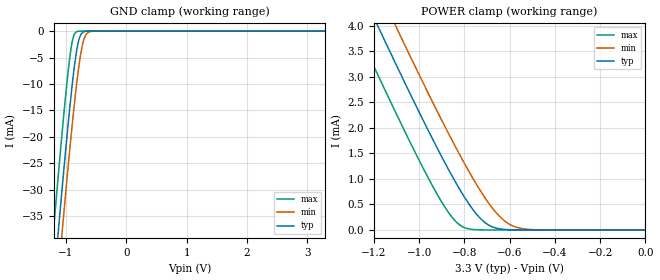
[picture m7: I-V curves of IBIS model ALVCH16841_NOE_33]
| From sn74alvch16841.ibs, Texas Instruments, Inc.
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[Model]   ALVCH16841_NOE_33
Model_type  Input
Vinl=0.8
Vinh=2.0
| variable   typ   min   max
C_comp   1.80pF   1.59pF   2.44pF
[Temperature Range]   40   100   -40
| Ambient temperature   25   85   -40
[Voltage range]   3.3   3   3.6
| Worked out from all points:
|   GND clamp passes 1 mA (typ) near -0.77 V on its own axis
|   POWER clamp passes 1 mA (typ) near -0.85 V on its own axis
[GND Clamp]
| ALVCH16841_NOE_33
|   Voltage   I(typ)   I(min)   I(max)
-3.3V     -341.5mA   -348.9mA   -332.3mA
-1.215V   -49.6mA    -57.88mA   -38.96mA
-1.185V   -45.62mA   -53.91mA   -34.98mA
-1.125V   -37.77mA   -46.06mA   -27.13mA
-1.065V   -30.08mA   -38.33mA   -19.51mA
-920mV    -12.75mA   -20.53mA   -3.718mA
-875mV    -8.124mA   -15.45mA   -1.065mA
-825mV    -3.922mA   -10.26mA   -137.1uA
-775mV    -1.291mA   -5.83mA    -13.57uA
-715mV    -205.4uA   -2.128mA   -808.5nA
-585mV    -2.266uA   -70.82uA   -1.783nA
3.3V      6.304pA    9.258pA    5.93pA
[POWER Clamp]
| ALVCH16841_NOE_33
|   Voltage   I(typ)   I(min)   I(max)
-3.3V     24.83mA    25.52mA    23.96mA
-1.275V   4.872mA    5.61mA     3.918mA
-1.185V   4.018mA    4.758mA    3.062mA
-1.105V   3.269mA    4.008mA    2.314mA
-1.07V    2.945mA    3.683mA    1.992mA
-940mV    1.776mA    2.501mA    856.4uA
-845mV    982.9uA    1.676mA    200.1uA
-795mV    611.2uA    1.266mA    38.41uA
-725mV    207uA      738.7uA    1.527uA
-625mV    11.21uA    186.8uA    11.91nA
-510mV    181.6nA    9.688uA    52.91pA
-48.03fV  6.303pA    7.801pA    6.677pA
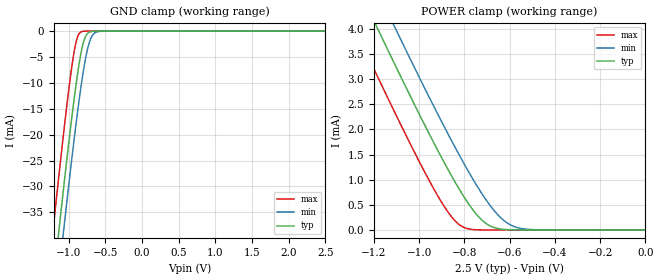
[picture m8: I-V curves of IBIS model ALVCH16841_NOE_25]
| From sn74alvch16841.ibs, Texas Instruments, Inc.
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[Model]   ALVCH16841_NOE_25
Model_type  Input
Vinl=0.7
Vinh=1.7
| variable   typ   min   max
C_comp   1.77pF   1.62pF   2.14pF
[Temperature Range]   40   100   -40
| Ambient temperature   25   85   -40
[Voltage range]   2.5   2.3   2.7
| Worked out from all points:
|   GND clamp passes 1 mA (typ) near -0.77 V on its own axis
|   POWER clamp passes 1 mA (typ) near -0.85 V on its own axis
[GND Clamp]
| ALVCH16841_NOE_25
|   Voltage   I(typ)   I(min)   I(max)
-2.5V     -228.1mA   -235.8mA   -218.5mA
-1.23V    -51.59mA   -59.87mA   -40.97mA
-1.2V     -47.61mA   -55.9mA    -36.97mA
-1.13V    -38.42mA   -46.71mA   -27.77mA
-1.07V    -30.71mA   -38.96mA   -20.13mA
-925mV    -13.29mA   -21.11mA   -4.122mA
-880mV    -8.606mA   -15.99mA   -1.263mA
-830mV    -4.281mA   -10.75mA   -171.6uA
-780mV    -1.472mA   -6.227mA   -17.15uA
-720mV    -242.5uA   -2.354mA   -1.023uA
-600mV    -3.832uA   -109.2uA   -3.608nA
2.5V      4.713pA    7.577pA    4.389pA
[POWER Clamp]
| ALVCH16841_NOE_25
|   Voltage   I(typ)   I(min)   I(max)
-2.5V     16.88mA    17.58mA    15.98mA
-1.3V     5.111mA    5.849mA    4.158mA
-1.255V   4.681mA    5.42mA     3.727mA
-1.18V    3.971mA    4.711mA    3.015mA
-1.11V    3.316mA    4.055mA    2.36mA
-940mV    1.776mA    2.501mA    856.4uA
-845mV    982.9uA    1.676mA    200.1uA
-795mV    611.2uA    1.266mA    38.41uA
-725mV    207uA      738.7uA    1.527uA
-625mV    11.21uA    186.8uA    11.91nA
-510mV    181.6nA    9.688uA    51.12pA
-31.15fV  4.712pA    6.41pA     4.886pA
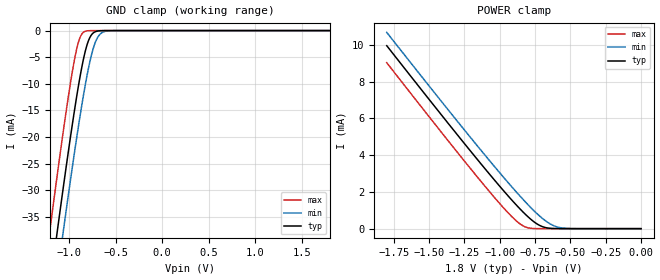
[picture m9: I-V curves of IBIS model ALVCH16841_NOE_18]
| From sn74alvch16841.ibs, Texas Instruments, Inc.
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[Model]   ALVCH16841_NOE_18
Model_type  Input
Vinl=0.5775
Vinh=1.2675
| variable   typ   min   max
C_comp   1.74pF   1.61pF   2.09pF
[Temperature Range]   40   100   -40
| Ambient temperature   25   85   -40
[Voltage range]   1.8   1.65   1.95
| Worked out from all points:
|   GND clamp passes 1 mA (typ) near -0.77 V on its own axis
|   POWER clamp passes 1 mA (typ) near -0.85 V on its own axis
[GND Clamp]
| ALVCH16841_NOE_18
|   Voltage   I(typ)   I(min)   I(max)
-1.8V     -129.8mA   -137.8mA   -119.7mA
-1.205V   -48.27mA   -56.56mA   -37.63mA
-1.125V   -37.77mA   -46.06mA   -27.13mA
-1.06V    -29.44mA   -37.69mA   -18.89mA
-980mV    -19.61mA   -27.69mA   -9.485mA
-925mV    -13.29mA   -21.11mA   -4.122mA
-880mV    -8.606mA   -15.99mA   -1.263mA
-835mV    -4.656mA   -11.25mA   -214.1uA
-780mV    -1.472mA   -6.227mA   -17.15uA
-725mV    -285.9uA   -2.596mA   -1.294uA
-615mV    -6.479uA   -167.8uA   -7.305nA
1.8V      3.326pA    6.142pA    3.026pA
[POWER Clamp]
| ALVCH16841_NOE_18
|   Voltage   I(typ)   I(min)   I(max)
-1.8V     9.965mA    10.69mA    9.037mA
-1.38V    5.878mA    6.614mA    4.929mA
-1.105V   3.269mA    4.008mA    2.314mA
-940mV    1.776mA    2.501mA    856.4uA
-885mV    1.307mA    2.018mA    440uA
-845mV    982.9uA    1.676mA    200.1uA
-795mV    611.2uA    1.266mA    38.41uA
-715mV    166.7uA    670.1uA    941.7nA
-645mV    22.22uA    268.3uA    31.48nA
-585mV    2.717uA    77.14uA    1.709nA
-485mV    73.51nA    4.604uA    18.27pA
-16.28fV  3.325pA    5.122pA    3.398pA
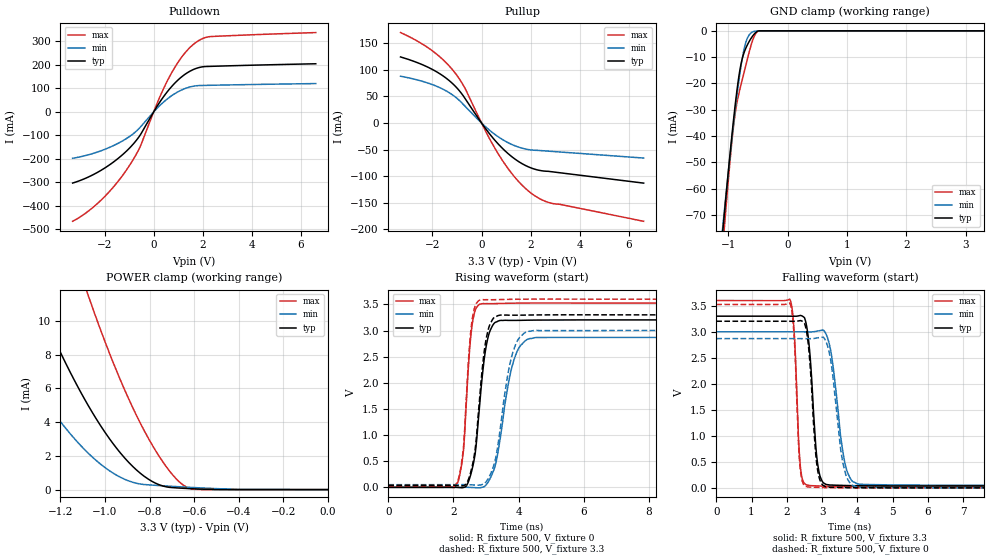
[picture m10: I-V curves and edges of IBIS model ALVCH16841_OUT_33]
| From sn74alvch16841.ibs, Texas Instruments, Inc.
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[Model]   ALVCH16841_OUT_33
Model_type  3-state
Enable   Active-Low
Vref =   0
Rref =   500
Cref =   50p
Vmeas =   1.5
| variable   typ   min   max
C_comp   7.10pF   6.17pF   8.40pF
| C_pullup   8.27pF   6.77pF   9.37pF
| C_pulldown   11.41pF   8.43pF   15.44pF
| C_tri-state   7.10pF   6.17pF   8.40pF
[Temperature Range]   40   100   -40
| Ambient temperature   25   85   -40
[Voltage range]   3.3   3   3.6
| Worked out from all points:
|   slope of the pulldown table from 0 to 0.495 V, typ, clamps not added: 6.36 ohm
|   slope of the pullup table from 0 to 0.495 V, typ, clamps not added: 16.5 ohm
|   GND clamp passes 1 mA (typ) near -0.55 V on its own axis
|   POWER clamp passes 1 mA (typ) near -0.84 V on its own axis
|   rising waveform, R_fixture 500, V_fixture 0: 20-80 % time 304ps typ, 456ps min, 215ps max; typ from 0 V to 3.2 V
|   falling waveform, R_fixture 500, V_fixture 3.3: 20-80 % time 191ps typ, 305ps min, 130ps max; typ from 3.3 V to 0.037 V
|   rising waveform, R_fixture 500, V_fixture 3.3: 20-80 % time 298ps typ, 430ps min, 213ps max; typ from 0.037 V to 3.3 V
|   falling waveform, R_fixture 500, V_fixture 0: 20-80 % time 185ps typ, 288ps min, 128ps max; typ from 3.2 V to 0 V
[GND Clamp]
| ALVCH16841_OUT_33
|   Voltage   I(typ)   I(min)   I(max)
-3.3V     -701.5mA   -639.5mA   -795.8mA
-1.09V    -75.9mA    -74.07mA   -82.03mA
-1.07V    -70.95mA   -69.58mA   -76.41mA
-1.05V    -66.05mA   -65.13mA   -70.87mA
-915mV    -34.94mA   -36.55mA   -37.33mA
-865mV    -24.93mA   -26.91mA   -28.93mA
-815mV    -16.6mA    -18.16mA   -23.39mA
-770mV    -11.23mA   -11.42mA   -19.2mA
-710mV    -6.971mA   -4.944mA   -13.82mA
-585mV    -1.88mA    -366.9uA   -3.413mA
-480mV    -19.21uA   -57.93uA   -14.88uA
3.3V      114.4pA    942nA      51.31pA
[POWER Clamp]
| ALVCH16841_OUT_33
|   Voltage   I(typ)   I(min)   I(max)
-3.3V     106mA      74.09mA    151.6mA
-1.545V   19.46mA    11.49mA    33.45mA
-1.32V    11.68mA    6.284mA    22.02mA
-1.295V   10.9mA     5.78mA     20.85mA
-1.195V   7.991mA    3.942mA    16.37mA
-1.075V   4.975mA    2.155mA    11.49mA
-965mV    2.743mA    987.8uA    7.581mA
-860mV    1.177mA    378.5uA    4.425mA
-760mV    302.3uA    241.6uA    2.031mA
-660mV    86.32uA    163.8uA    380.1uA
-605mV    48.5uA     124.6uA    22.06uA
-48.03fV  114.4pA    359.8pA    62.68pA
[Pulldown]
| ALVCH16841_OUT_33
|   Voltage   I(typ)   I(min)   I(max)
-3.3V     -302.4mA   -196.9mA   -465.1mA
-2.735V   -280.4mA   -184.4mA   -427.8mA
-2.16V    -249.3mA   -165.8mA   -377mA
-1.61V    -210.9mA   -141.8mA   -315.8mA
-1.105V   -166.3mA   -112.9mA   -246.6mA
-565mV    -100.8mA   -67.07mA   -151.3mA
185mV     31.43mA    20.51mA    47.78mA
665mV     100mA      64.12mA    153.8mA
1.17V     151.9mA    95.01mA    237.4mA
1.67V     182.8mA    110.5mA    291.9mA
2.31V     194mA      113.5mA    320.7mA
6.6V      205mA      120.8mA    337.8mA
[Pullup]
| ALVCH16841_OUT_33
|   Voltage   I(typ)   I(min)   I(max)
-3.3V     124.6mA    88.26mA    170.5mA
-2.055V   102.2mA    73.29mA    137.8mA
-1.565V   88.69mA    63.61mA    119.2mA
-1.15V    73.01mA    51.93mA    98.57mA
-690mV    47.45mA    32.47mA    66.81mA
180mV     -11.59mA   -7.766mA   -16.76mA
755mV     -43.3mA    -28.29mA   -63.76mA
1.375V    -68.47mA   -43.2mA    -103.3mA
1.995V    -84.31mA   -50.62mA   -131.4mA
2.4V      -89.62mA   -51.95mA   -143.5mA
2.81V     -91.58mA   -53.32mA   -150.8mA
6.6V      -113.3mA   -66.05mA   -185.3mA
[Ramp]
| ALVCH16841_OUT_33
| variable   typ   min   max
dV/dt_r   1.93/3.10E-10   1.73/4.77E-10   2.12/2.18E-10
dV/dt_f   1.97/1.99E-10   1.79/3.22E-10   2.16/1.35E-10
R_load = 500
[Rising Waveform]
| ALVCH16841_OUT_33
R_fixture =   500
C_fixture =   0
L_fixture =   0
V_fixture =   0
V_fixture_min = 0
V_fixture_max = 0
|   Time   V(typ)   V(min)   V(max)
0s        369.5pV    1.242nV    265.6pV
2.115ns   -510.1uV   942.6uV    70.82mV
2.31ns    -2.365mV   1.738mV    720.3mV
2.575ns   348.6mV    -2.666mV   3.111V
2.69ns    762.4mV    -6.512mV   3.42V
2.895ns   2.176V     3.64mV     3.515V
3.21ns    3.103V     284.6mV    3.515V
3.88ns    3.194V     2.475V     3.524V
4.54ns    3.2V       2.868V     3.527V
45ns      3.202V     2.869V     3.526V
[Falling Waveform]
| ALVCH16841_OUT_33
R_fixture =   500
C_fixture =   0
L_fixture =   0
V_fixture =   3.3
V_fixture_min = 3
V_fixture_max = 3.6
|   Time   V(typ)   V(min)   V(max)
0s        3.3V       3V         3.6V
2.085ns   3.299V     3V         3.624V
2.21ns    3.299V     3V         2.966V
2.39ns    3.313V     2.999V     364.4mV
2.665ns   2.476V     2.997V     43.49mV
2.95ns    203.9mV    3.024V     35.21mV
3.24ns    53.7mV     2.649V     30.71mV
3.67ns    45.04mV    404.4mV    27.75mV
4.04ns    40.19mV    71.15mV    26.8mV
45ns      37.06mV    51.27mV    26.72mV
[Rising Waveform]
| ALVCH16841_OUT_33
R_fixture =   500
C_fixture =   0
L_fixture =   0
V_fixture =   3.3
V_fixture_min = 3
V_fixture_max = 3.6
|   Time   V(typ)   V(min)   V(max)
0s        37.06mV    51.27mV    26.72mV
2.115ns   35.98mV    51.95mV    99.38mV
2.31ns    35.04mV    52.32mV    779.3mV
2.57ns    389.1mV    47.75mV    3.188V
2.685ns   825mV      44.26mV    3.5V
2.885ns   2.262V     55.04mV    3.591V
3.195ns   3.205V     339.8mV    3.589V
3.84ns    3.294V     2.611V     3.598V
4.475ns   3.298V     3.001V     3.601V
45ns      3.3V       3V         3.6V
[Falling Waveform]
| ALVCH16841_OUT_33
R_fixture =   500
C_fixture =   0
L_fixture =   0
V_fixture =   0
V_fixture_min = 0
V_fixture_max = 0
|   Time   V(typ)   V(min)   V(max)
0s        3.202V     2.869V     3.526V
2.085ns   3.202V     2.869V     3.549V
2.21ns    3.201V     2.868V     2.866V
2.375ns   3.215V     2.868V     395.8mV
2.595ns   2.832V     2.867V     17.23mV
2.85ns    445mV      2.88V      9.79mV
3.13ns    16.42mV    2.778V     4.813mV
3.605ns   7.169mV    425.9mV    1.076mV
4.02ns    2.687mV    11.45mV    64.48uV
45ns      110.9nV    3.83nV     409pV
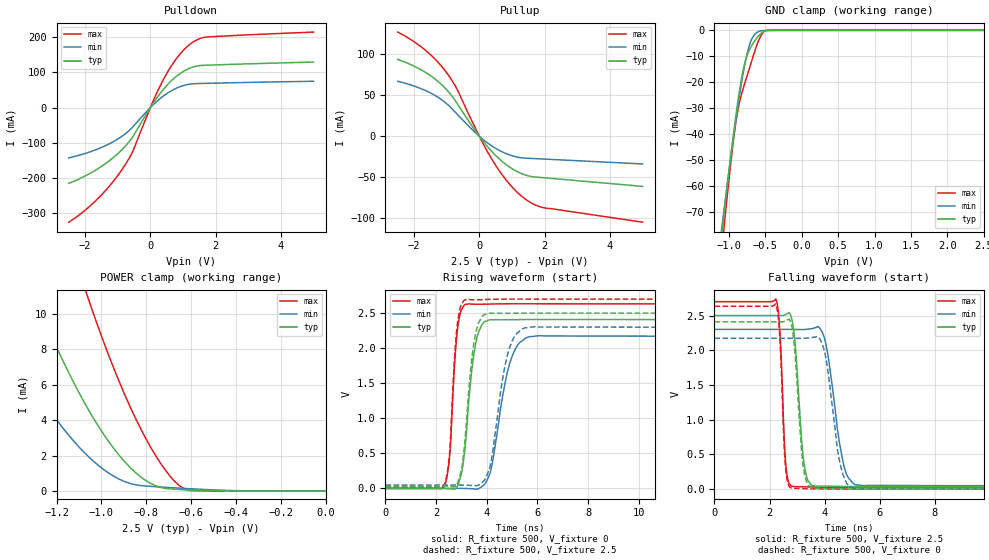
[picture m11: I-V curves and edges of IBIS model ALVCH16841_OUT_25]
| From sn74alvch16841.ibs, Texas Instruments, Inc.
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[Model]   ALVCH16841_OUT_25
Model_type  3-state
Enable   Active-Low
Vref =   0
Rref =   500
Cref =   30p
Vmeas =   1.25
| variable   typ   min   max
C_comp   7.35pF   6.43pF   8.45pF
| C_pullup   8.53pF   7.04pF   9.34pF
| C_pulldown   11.69pF   8.53pF   15.54pF
| C_tri-state   7.35pF   6.43pF   8.45pF
[Temperature Range]   40   100   -40
| Ambient temperature   25   85   -40
[Voltage range]   2.5   2.3   2.7
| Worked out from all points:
|   slope of the pulldown table from 0 to 0.375 V, typ, clamps not added: 7.66 ohm
|   slope of the pullup table from 0 to 0.375 V, typ, clamps not added: 20.6 ohm
|   GND clamp passes 1 mA (typ) near -0.55 V on its own axis
|   POWER clamp passes 1 mA (typ) near -0.84 V on its own axis
|   rising waveform, R_fixture 500, V_fixture 0: 20-80 % time 384ps typ, 614ps min, 250ps max; typ from 0 V to 2.41 V
|   falling waveform, R_fixture 500, V_fixture 2.5: 20-80 % time 257ps typ, 464ps min, 164ps max; typ from 2.5 V to 0.034 V
|   rising waveform, R_fixture 500, V_fixture 2.5: 20-80 % time 369ps typ, 557ps min, 246ps max; typ from 0.034 V to 2.5 V
|   falling waveform, R_fixture 500, V_fixture 0: 20-80 % time 247ps typ, 420ps min, 161ps max; typ from 2.41 V to 0 V
[GND Clamp]
| ALVCH16841_OUT_25
|   Voltage   I(typ)   I(min)   I(max)
-2.5V     -467.6mA   -428.1mA   -528.9mA
-1.095V   -77.15mA   -75.2mA    -83.44mA
-1.08V    -73.42mA   -71.82mA   -79.21mA
-1.06V    -68.5mA    -67.35mA   -73.63mA
-920mV    -36.01mA   -37.55mA   -38.35mA
-870mV    -25.87mA   -27.84mA   -29.62mA
-815mV    -16.6mA    -18.16mA   -23.39mA
-770mV    -11.23mA   -11.42mA   -19.2mA
-710mV    -6.971mA   -4.944mA   -13.82mA
-595mV    -2.192mA   -484.1uA   -4.058mA
-480mV    -19.21uA   -57.93uA   -14.88uA
2.5V      83.8pA     43.75nA    39.19pA
[POWER Clamp]
| ALVCH16841_OUT_25
|   Voltage   I(typ)   I(min)   I(max)
-2.5V     62.78mA    42.4mA     93.4mA
-1.535V   19.08mA    11.24mA    32.91mA
-1.515V   18.34mA    10.73mA    31.84mA
-1.295V   10.9mA     5.78mA     20.85mA
-1.165V   7.185mA    3.45mA     15.09mA
-1.06V    4.638mA    1.967mA    10.93mA
-950mV    2.483mA    868.5uA    7.093mA
-845mV    1.005mA    337.3uA    4.026mA
-745mV    230.8uA    229.2uA    1.729mA
-655mV    82.47uA    160.2uA    326.5uA
-600mV    45.53uA    121.2uA    16.21uA
-31.15fV  83.8pA     317.5pA    46.7pA
[Pulldown]
| ALVCH16841_OUT_25
|   Voltage   I(typ)   I(min)   I(max)
-2.5V     -214.5mA   -142.4mA   -324.7mA
-1.625V   -174.1mA   -117.7mA   -259.4mA
-1.225V   -148.2mA   -100.9mA   -219.1mA
-870mV    -119.2mA   -81.23mA   -175.5mA
-550mV    -84.06mA   -55.7mA    -125.8mA
75mV      10.83mA    7.022mA    16.48mA
430mV     55.09mA    35.04mA    84.84mA
820mV     90.47mA    55.98mA    141.7mA
1.215V    112.2mA    66.71mA    179.9mA
1.465V    118.6mA    68.28mA    193.9mA
1.72V     120.2mA    68.88mA    200.2mA
5V        129.2mA    74.77mA    214.1mA
[Pullup]
| ALVCH16841_OUT_25
|   Voltage   I(typ)   I(min)   I(max)
-2.5V     93.89mA    67.09mA    127.2mA
-1.675V   78.56mA    56.27mA    105.7mA
-1.335V   69.15mA    49.28mA    93.27mA
-1.035V   58.23mA    40.89mA    79.35mA
-685mV    40.38mA    27.22mA    57.59mA
15mV      -812.9uA   -531.7uA   -1.2mA
420mV     -20.15mA   -12.8mA    -30.36mA
885mV     -36.42mA   -22.17mA   -56.52mA
1.355V    -46.47mA   -26.53mA   -75.01mA
1.67V     -49.6mA    -27.19mA   -82.95mA
1.985V    -50.63mA   -27.82mA   -87.32mA
5V        -61.14mA   -33.76mA   -104.8mA
[Ramp]
| ALVCH16841_OUT_25
| variable   typ   min   max
dV/dt_r   1.45/3.97E-10   1.31/6.52E-10   1.58/2.54E-10
dV/dt_f   1.51/2.77E-10   1.38/5.02E-10   1.63/1.74E-10
R_load = 500
[Rising Waveform]
| ALVCH16841_OUT_25
R_fixture =   500
C_fixture =   0
L_fixture =   0
V_fixture =   0
V_fixture_min = 0
V_fixture_max = 0
|   Time   V(typ)   V(min)   V(max)
0s        334.1pV    1.357nV    238.1pV
2.345ns   737.2uV    241.2uV    41.53mV
2.55ns    -3.701mV   758.7uV    537.7mV
2.835ns   33.65mV    1.019mV    2.243V
3.16ns    661.4mV    -188.9uV   2.626V
3.46ns    1.846V     -5.921mV   2.628V
3.79ns    2.323V     21.54mV    2.627V
4.935ns   2.407V     1.821V     2.634V
5.7ns     2.409V     2.166V     2.634V
45ns      2.409V     2.172V     2.633V
[Falling Waveform]
| ALVCH16841_OUT_25
R_fixture =   500
C_fixture =   0
L_fixture =   0
V_fixture =   2.5
V_fixture_min = 2.3
V_fixture_max = 2.7
|   Time   V(typ)   V(min)   V(max)
0s        2.5V       2.3V       2.7V
2.235ns   2.499V     2.3V       2.73V
2.38ns    2.498V     2.3V       2.24V
2.585ns   2.511V     2.3V       381.2mV
2.815ns   2.441V     2.299V     36.76mV
3.235ns   422.3mV    2.298V     31.06mV
3.57ns    44.91mV    2.314V     27.21mV
4ns       41.12mV    2.173V     24.66mV
5.16ns    33.84mV    56.16mV    23.65mV
45ns      33.7mV     47.62mV    23.99mV
[Rising Waveform]
| ALVCH16841_OUT_25
R_fixture =   500
C_fixture =   0
L_fixture =   0
V_fixture =   2.5
V_fixture_min = 2.3
V_fixture_max = 2.7
|   Time   V(typ)   V(min)   V(max)
0s        33.7mV     47.62mV    23.99mV
2.345ns   33.8mV     47.81mV    67.78mV
2.535ns   30mV       48.1mV     529.5mV
2.83ns    68.15mV    47.85mV    2.324V
3.15ns    736.3mV    46.33mV    2.692V
3.69ns    2.373V     52.02mV    2.692V
4.125ns   2.501V     309.7mV    2.697V
4.86ns    2.498V     1.964V     2.701V
5.535ns   2.5V       2.293V     2.701V
45ns      2.5V       2.3V       2.7V
[Falling Waveform]
| ALVCH16841_OUT_25
R_fixture =   500
C_fixture =   0
L_fixture =   0
V_fixture =   0
V_fixture_min = 0
V_fixture_max = 0
|   Time   V(typ)   V(min)   V(max)
0s        2.409V     2.172V     2.633V
2.23ns    2.408V     2.172V     2.666V
2.37ns    2.408V     2.172V     2.202V
2.58ns    2.42V      2.172V     319.9mV
2.81ns    2.342V     2.171V     9.939mV
3.21ns    369.8mV    2.171V     6.457mV
3.54ns    10.6mV     2.182V     2.858mV
3.995ns   5.85mV     1.99V      498uV
5.125ns   -17.3uV    -2.403mV   -297.9uV
45ns      -205.3pV   814.5pV    1.515nV
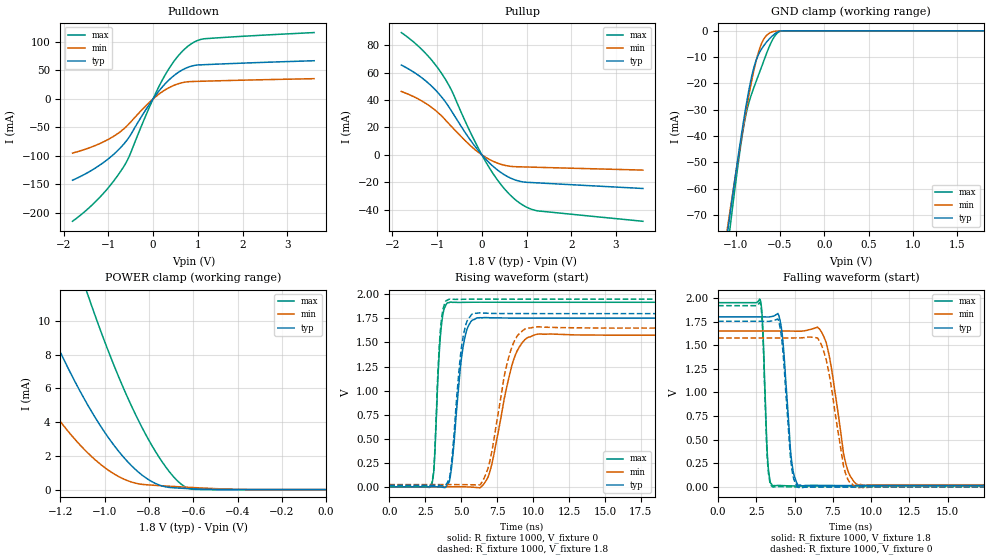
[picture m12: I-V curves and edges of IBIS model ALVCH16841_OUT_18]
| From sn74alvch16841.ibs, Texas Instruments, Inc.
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[Model]   ALVCH16841_OUT_18
Model_type  3-state
Enable   Active-Low
Vref =   0
Rref =   1000
Cref =   30p
Vmeas =   0.9
| variable   typ   min   max
C_comp   7.65pF   6.70pF   8.54pF
| C_pullup   8.71pF   7.16pF   9.45pF
| C_pulldown   12.20pF   8.68pF   16.08pF
| C_tri-state   7.65pF   6.70pF   8.54pF
[Temperature Range]   40   100   -40
| Ambient temperature   25   85   -40
[Voltage range]   1.8   1.65   1.95
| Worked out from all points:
|   slope of the pulldown table from 0 to 0.27 V, typ, clamps not added: 10.2 ohm
|   slope of the pullup table from 0 to 0.27 V, typ, clamps not added: 30.2 ohm
|   GND clamp passes 1 mA (typ) near -0.55 V on its own axis
|   POWER clamp passes 1 mA (typ) near -0.84 V on its own axis
|   rising waveform, R_fixture 1000, V_fixture 0: 20-80 % time 644ps typ, 1.28ns min, 360ps max; typ from 0 V to 1.75 V
|   falling waveform, R_fixture 1000, V_fixture 1.8: 20-80 % time 455ps typ, 875ps min, 248ps max; typ from 1.8 V to 0.016 V
|   rising waveform, R_fixture 1000, V_fixture 1.8: 20-80 % time 613ps typ, 1.16ns min, 348ps max; typ from 0.016 V to 1.8 V
|   falling waveform, R_fixture 1000, V_fixture 0: 20-80 % time 459ps typ, 927ps min, 244ps max; typ from 1.75 V to 0 V
[GND Clamp]
| ALVCH16841_OUT_18
|   Voltage   I(typ)   I(min)   I(max)
-1.8V     -267.3mA   -247.1mA   -300.4mA
-1.09V    -75.9mA    -74.07mA   -82.03mA
-1.075V   -72.18mA   -70.7mA    -77.81mA
-1.055V   -67.27mA   -66.24mA   -72.25mA
-920mV    -36.01mA   -37.55mA   -38.35mA
-875mV    -26.83mA   -28.78mA   -30.33mA
-820mV    -17.33mA   -18.99mA   -23.88mA
-775mV    -11.72mA   -12.1mA    -19.66mA
-720mV    -7.532mA   -5.789mA   -14.72mA
-615mV    -2.864mA   -799uA     -5.494mA
-485mV    -24.85uA   -61.55uA   -23.48uA
1.8V      60.47pA    9.416nA    28.01pA
[POWER Clamp]
| ALVCH16841_OUT_18
|   Voltage   I(typ)   I(min)   I(max)
-1.8V     29.67mA    18.6mA     47.93mA
-1.545V   19.46mA    11.49mA    33.45mA
-1.31V    11.36mA    6.08mA     21.55mA
-1.19V    7.854mA    3.858mA    16.15mA
-1.07V    4.862mA    2.091mA    11.3mA
-925mV    2.076mA    692.6uA    6.307mA
-850mV    1.061mA    349.7uA    4.157mA
-770mV    359.1uA    250.1uA    2.24mA
-695mV    116.6uA    189.9uA    848.9uA
-635mV    67.93uA    145.7uA    152.5uA
-585mV    37.09uA    111uA      9.499uA
-16.28fV  60.47pA    281.6pA    33.61pA
[Pulldown]
| ALVCH16841_OUT_18
|   Voltage   I(typ)   I(min)   I(max)
-1.8V     -142.5mA   -94.94mA   -214.6mA
-1.19V    -116mA     -78.24mA   -172.4mA
-925mV    -100.2mA   -67.56mA   -148.5mA
-690mV    -82.3mA    -54.81mA   -122.9mA
-535mV    -66.97mA   -43.32mA   -101mA
-105mV    -12.13mA   -7.634mA   -18.73mA
200mV     20.41mA    12.38mA    32.16mA
490mV     42.45mA    24.65mA    68.46mA
785mV     55.72mA    30.25mA    92.88mA
970mV     59.35mA    30.84mA    101.8mA
1.155V    60.2mA     31.26mA    105.7mA
3.6V      67.09mA    35.62mA    116.5mA
[Pullup]
| ALVCH16841_OUT_18
|   Voltage   I(typ)   I(min)   I(max)
-1.8V     65.54mA    46.25mA    89.25mA
-1.32V    55.67mA    38.89mA    76.19mA
-1.11V    49.72mA    34.29mA    68.65mA
-920mV    43.05mA    29.01mA    60.43mA
-685mV    32.34mA    20.89mA    47.55mA
-250mV    10.47mA    6.526mA    16.03mA
115mV     -4.131mA   -2.38mA    -6.642mA
450mV     -13.44mA   -7.131mA   -22.64mA
790mV     -18.81mA   -8.709mA   -33.84mA
1.02V     -20.1mA    -8.918mA   -38.54mA
1.25V     -20.5mA    -9.124mA   -40.92mA
3.6V      -24.58mA   -11.14mA   -48.53mA
[Ramp]
| ALVCH16841_OUT_18
| variable   typ   min   max
dV/dt_r   1.06/6.75E-10   0.96/1.34E-09   1.16/3.79E-10
dV/dt_f   1.09/4.89E-10   1.00/9.53E-10   1.19/2.70E-10
R_load = 1000
[Rising Waveform]
| ALVCH16841_OUT_18
R_fixture =   1000
C_fixture =   0
L_fixture =   0
V_fixture =   0
V_fixture_min = 0
V_fixture_max = 0
|   Time   V(typ)   V(min)   V(max)
0s        316.9pV    1.692nV    220.5pV
2.965ns   725.3uV    -66.5uV    27.12mV
3.58ns    -2.054mV   244.7uV    1.606V
4.075ns   28.8mV     517.5uV    1.915V
5.175ns   1.489V     -117.9uV   1.917V
6.14ns    1.756V     -8.063mV   1.919V
7.005ns   1.757V     162.4mV    1.918V
8.745ns   1.754V     1.36V      1.918V
10.23ns   1.753V     1.584V     1.918V
50ns      1.753V     1.576V     1.918V
[Falling Waveform]
| ALVCH16841_OUT_18
R_fixture =   1000
C_fixture =   0
L_fixture =   0
V_fixture =   1.8
V_fixture_min = 1.65
V_fixture_max = 1.95
|   Time   V(typ)   V(min)   V(max)
0s        1.8V       1.65V      1.95V
2.765ns   1.8V       1.65V      1.973V
3.25ns    1.798V     1.65V      269.4mV
3.595ns   1.807V     1.65V      12.26mV
4.145ns   1.676V     1.65V      15.39mV
4.775ns   322.3mV    1.649V     11.81mV
5.275ns   17.34mV    1.648V     10.8mV
7ns       16.41mV    1.556V     10.88mV
9.14ns    15.7mV     23.53mV    11.08mV
50ns      15.91mV    23.52mV    11.08mV
[Rising Waveform]
| ALVCH16841_OUT_18
R_fixture =   1000
C_fixture =   0
L_fixture =   0
V_fixture =   1.8
V_fixture_min = 1.65
V_fixture_max = 1.95
|   Time   V(typ)   V(min)   V(max)
0s        15.91mV    23.52mV    11.08mV
2.965ns   16.32mV    23.49mV    40.48mV
3.575ns   14.07mV    23.73mV    1.658V
4.145ns   74.16mV    23.71mV    1.949V
5.07ns    1.497V     22.77mV    1.949V
5.89ns    1.805V     20.88mV    1.951V
6.875ns   1.804V     194.3mV    1.951V
8.475ns   1.8V       1.429V     1.95V
9.61ns    1.8V       1.65V      1.95V
50ns      1.8V       1.65V      1.95V
[Falling Waveform]
| ALVCH16841_OUT_18
R_fixture =   1000
C_fixture =   0
L_fixture =   0
V_fixture =   0
V_fixture_min = 0
V_fixture_max = 0
|   Time   V(typ)   V(min)   V(max)
0s        1.753V     1.576V     1.918V
2.76ns    1.753V     1.576V     1.94V
3.24ns    1.752V     1.576V     247.9mV
3.59ns    1.759V     1.576V     -1.171mV
4.09ns    1.648V     1.576V     3.424mV
4.76ns    268.3mV    1.576V     611.9uV
5.26ns    -4.899mV   1.577V     -219.4uV
6.79ns    465uV      1.487V     -200.7uV
9.085ns   -198uV     -8.381mV   -7.045uV
50ns      3.423nV    7.093nV    -153.7pV
